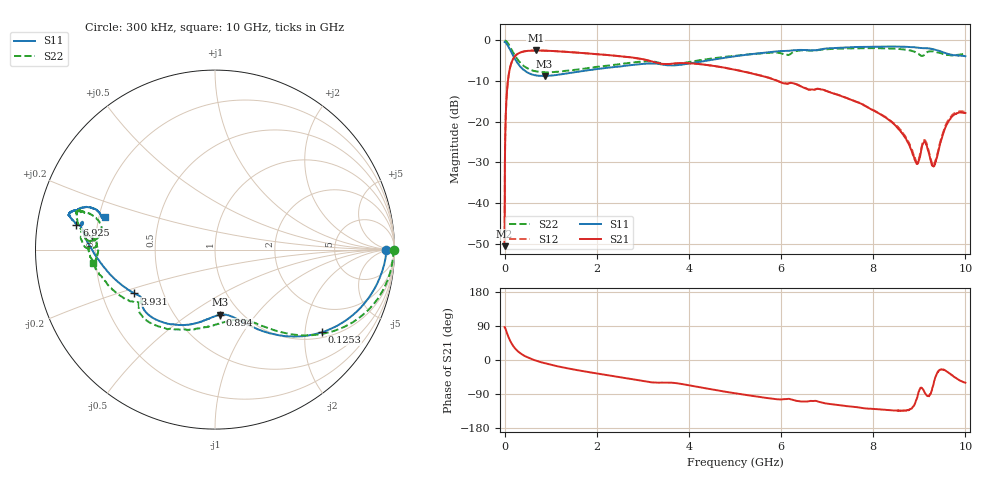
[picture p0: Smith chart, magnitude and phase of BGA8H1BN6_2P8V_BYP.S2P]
!Agilent Technologies,E5071C,MY46316587,B.13.01
!Date: Tue Nov 28 12:35:40 2017
!Data & Calibration Information:
!Freq	S11:SOLT2(ON)	S21:SOLT2(ON)	S12:SOLT2(ON)	S22:SOLT2(ON)
!PortZ  Port1:50+j0  Port2:50+j0
!Above PortZ is port z conversion or system Z0 setting when saving the data.
!When reading, reference impedance value at option line is always used.
# Hz S RI R 50
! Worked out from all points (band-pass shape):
!   1601 points, 300 kHz to 10 GHz, reference 50 ohm
!   highest |S21| = -2.50 dB at 675.3 MHz (marker M1); lowest = -50.6 dB at 300 kHz (marker M2)
!   |S21| within 3 dB of the highest: 149.9 MHz to 3.29 GHz (3.14 GHz wide, 183 % of centre)
!   lowest |S11| = -8.8 dB at 869 MHz (marker M3), VSWR 2.14, Z = 40.5 - j33.8 ohm
!   |S11| at or under -10 dB: nowhere
!   |S22| runs from -7.9 to 0.0 dB; largest |S21 - S12| = 0.0061
!   S11 on the Smith chart (normalised r, x): 300 kHz: 42, -4; 125.3 MHz: 1.15, -2.46; 894 MHz: 0.80, -0.67; 3.931 GHz: 0.34, -0.23; 6.925 GHz: 0.12, +0.09; 10 GHz: 0.23, +0.14
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300000  0.9544 -0.0043  0.000168 0.00295  0.000794 0.00307  0.9948 0.00026
5.654831e7  0.8327 -0.2992  0.0908 0.24  0.0911 0.2417  0.906 -0.2752
8.154756e7  0.7475 -0.3811  0.1676 0.3079  0.1685 0.309  0.8292 -0.3589
1.252962e8  0.5969 -0.4602  0.3094 0.3637  0.3111 0.3643  0.6868 -0.4441
3.190404e8  0.2236 -0.437  0.6575 0.2379  0.6588 0.2378  0.3181 -0.4446
6.752798e8  0.0671 -0.3644  0.7493 -0.0197  0.7499 -0.0202  0.1435 -0.3901
8.690239e8  0.0306 -0.3624  0.7387 -0.1102  0.7384 -0.1105  0.0952 -0.3939
8.940232e8  0.026 -0.3634  0.7355 -0.1201  0.7359 -0.1209  0.0892 -0.3949
1.669e9  -0.0918 -0.4065  0.6129 -0.3355  0.6145 -0.3344  -0.0772 -0.4383
2.756467e9  -0.2827 -0.4071  0.391 -0.4752  0.392 -0.4717  -0.3134 -0.4283
3.3377e9  -0.4047 -0.3144  0.2623 -0.4514  0.2604 -0.4491  -0.4242 -0.3187
3.931432e9  -0.4486 -0.2442  0.2199 -0.4755  0.2173 -0.4725  -0.4426 -0.2953
5.00015e9  -0.6308 -0.0823  0.0178 -0.4332  0.0178 -0.4337  -0.6211 -0.1624
6.66885e9  -0.7368 0.1461  -0.0771 -0.2363  -0.0771 -0.2376  -0.7394 0.1102
6.925092e9  -0.7726 0.1396  -0.0977 -0.2257  -0.098 -0.2257  -0.7601 0.1318
8.33755e9  -0.815 0.1949  -0.0707 -0.0782  -0.072 -0.0789  -0.7624 0.217
8.68129e9  -0.8071 0.2063  -0.0446 -0.0474  -0.0468 -0.0485  -0.7391 0.2127
8.931282e9  -0.7862 0.2163  -0.00855 -0.0302  -0.0083 -0.032  -0.6802 0.1892
9.118776e9  -0.7705 0.2135  0.00336 -0.0569  0.00389 -0.0592  -0.6739 0.0529
9.300021e9  -0.7403 0.2321  0.011 -0.0261  0.0119 -0.0275  -0.7279 0.0805
9.625011e9  -0.647 0.2097  0.0832 -0.0533  0.0873 -0.0555  -0.6595 0.0236
1e10  -0.6117 0.1789  0.064 -0.1106  0.0671 -0.1133  -0.6787 -0.077
